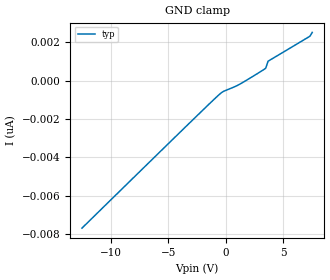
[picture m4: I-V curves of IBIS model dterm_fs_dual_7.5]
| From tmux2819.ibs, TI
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| dterm_fs_dual_7.5
[Model]   dterm_fs_dual_7.5
Model_type   Terminator
|   typ   min   max
C_comp   1.598234e-11   NA   NA
[Voltage Range]   7   NA   NA
[Temperature Range]   27   NA   NA
[GND Clamp Reference]   0   NA   NA
[GND Clamp]
|   Voltage   I(typ)   I(min)   I(max)
-12.5V    -7.685nA   NA         NA
-2.803V   -1.995nA   NA         NA
-378.8mV  -614.6pA   NA         NA
1.237V    -165pA     NA         NA
3.258V    571.5pA    NA         NA
3.46V     656.6pA    NA         NA
3.662V    1.021nA    NA         NA
7.298V    2.327nA    NA         NA
7.5V      2.527nA    NA         NA
